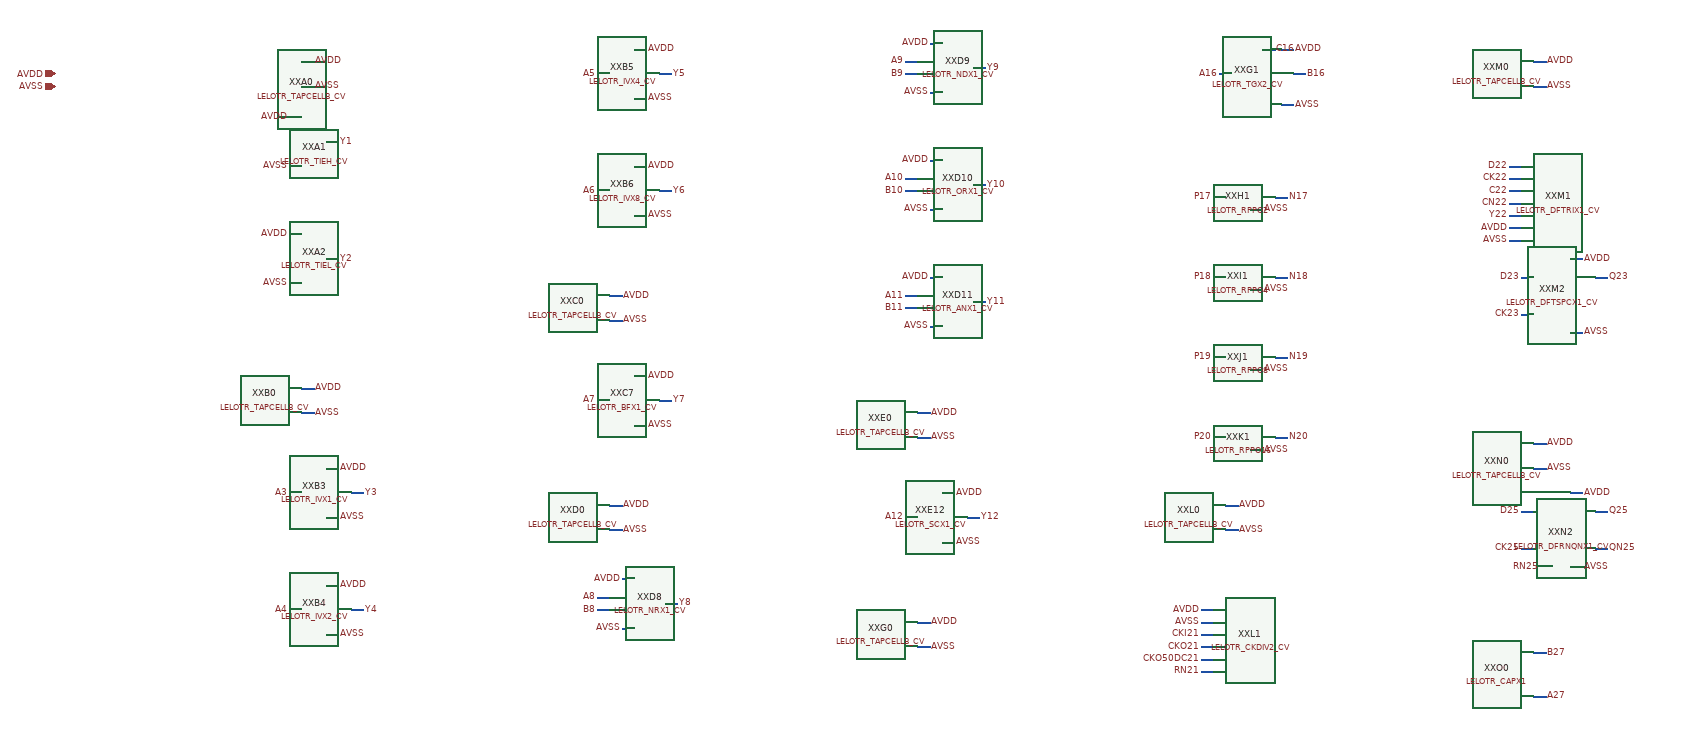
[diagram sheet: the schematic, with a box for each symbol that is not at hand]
v {xschem version=3.0.0 file_version=1.2 }
G {}
K {}
V {}
S {}
E {}
C {devices/iopin.sym} 0 0 0 0 {name=p0 lab=AVDD}
C {devices/iopin.sym} 0 20 0 0 {name=p1 lab=AVSS}
C {LELO_TR_IHP13G2/LELOTR_TAPCELLB_CV.sym} 400 0 0 0 {name=XXA0}
N 420.0 -20.0 400.0 -20.0 {lab=AVDD}
C {devices/lab_pin.sym} 420.0 -20.0 2 0 {name=l0 sig_type=std_logic lab=AVDD }
N 420.0 20.0 400.0 20.0 {lab=AVSS}
C {devices/lab_pin.sym} 420.0 20.0 2 0 {name=l1 sig_type=std_logic lab=AVSS }
C {LELO_TR_IHP13G2/LELOTR_TIEH_CV.sym} 400 150.0 0 0 {name=XXA1}
N 460.0 110.0 440.0 110.0 {lab=Y1}
C {devices/lab_pin.sym} 460.0 110.0 2 0 {name=l2 sig_type=std_logic lab=Y1 }
N 380.0 70.0 400.0 70.0 {lab=AVDD}
C {devices/lab_pin.sym} 380.0 70.0 0 0 {name=l3 sig_type=std_logic lab=AVDD }
N 380.0 150.0 400.0 150.0 {lab=AVSS}
C {devices/lab_pin.sym} 380.0 150.0 0 0 {name=l4 sig_type=std_logic lab=AVSS }
C {LELO_TR_IHP13G2/LELOTR_TIEL_CV.sym} 400 340.0 0 0 {name=XXA2}
N 460.0 300.0 440.0 300.0 {lab=Y2}
C {devices/lab_pin.sym} 460.0 300.0 2 0 {name=l5 sig_type=std_logic lab=Y2 }
N 380.0 260.0 400.0 260.0 {lab=AVDD}
C {devices/lab_pin.sym} 380.0 260.0 0 0 {name=l6 sig_type=std_logic lab=AVDD }
N 380.0 340.0 400.0 340.0 {lab=AVSS}
C {devices/lab_pin.sym} 380.0 340.0 0 0 {name=l7 sig_type=std_logic lab=AVSS }
C {LELO_TR_IHP13G2/LELOTR_TAPCELLB_CV.sym} 400 530.0 0 0 {name=XXB0}
N 420.0 510.0 400.0 510.0 {lab=AVDD}
C {devices/lab_pin.sym} 420.0 510.0 2 0 {name=l8 sig_type=std_logic lab=AVDD }
N 420.0 550.0 400.0 550.0 {lab=AVSS}
C {devices/lab_pin.sym} 420.0 550.0 2 0 {name=l9 sig_type=std_logic lab=AVSS }
C {LELO_TR_IHP13G2/LELOTR_IVX1_CV.sym} 400 680.0 0 0 {name=XXB3}
N 380.0 680.0 400.0 680.0 {lab=A3}
C {devices/lab_pin.sym} 380.0 680.0 0 0 {name=l10 sig_type=std_logic lab=A3 }
N 500.0 680.0 480.0 680.0 {lab=Y3}
C {devices/lab_pin.sym} 500.0 680.0 2 0 {name=l11 sig_type=std_logic lab=Y3 }
N 460.0 640.0 440.0 640.0 {lab=AVDD}
C {devices/lab_pin.sym} 460.0 640.0 2 0 {name=l12 sig_type=std_logic lab=AVDD }
N 460.0 720.0 440.0 720.0 {lab=AVSS}
C {devices/lab_pin.sym} 460.0 720.0 2 0 {name=l13 sig_type=std_logic lab=AVSS }
C {LELO_TR_IHP13G2/LELOTR_IVX2_CV.sym} 400 870.0 0 0 {name=XXB4}
N 380.0 870.0 400.0 870.0 {lab=A4}
C {devices/lab_pin.sym} 380.0 870.0 0 0 {name=l14 sig_type=std_logic lab=A4 }
N 500.0 870.0 480.0 870.0 {lab=Y4}
C {devices/lab_pin.sym} 500.0 870.0 2 0 {name=l15 sig_type=std_logic lab=Y4 }
N 460.0 830.0 440.0 830.0 {lab=AVDD}
C {devices/lab_pin.sym} 460.0 830.0 2 0 {name=l16 sig_type=std_logic lab=AVDD }
N 460.0 910.0 440.0 910.0 {lab=AVSS}
C {devices/lab_pin.sym} 460.0 910.0 2 0 {name=l17 sig_type=std_logic lab=AVSS }
C {LELO_TR_IHP13G2/LELOTR_IVX4_CV.sym} 900 0 0 0 {name=XXB5}
N 880.0 0.0 900.0 0.0 {lab=A5}
C {devices/lab_pin.sym} 880.0 0.0 0 0 {name=l18 sig_type=std_logic lab=A5 }
N 1000.0 0.0 980.0 0.0 {lab=Y5}
C {devices/lab_pin.sym} 1000.0 0.0 2 0 {name=l19 sig_type=std_logic lab=Y5 }
N 960.0 -40.0 940.0 -40.0 {lab=AVDD}
C {devices/lab_pin.sym} 960.0 -40.0 2 0 {name=l20 sig_type=std_logic lab=AVDD }
N 960.0 40.0 940.0 40.0 {lab=AVSS}
C {devices/lab_pin.sym} 960.0 40.0 2 0 {name=l21 sig_type=std_logic lab=AVSS }
C {LELO_TR_IHP13G2/LELOTR_IVX8_CV.sym} 900 190.0 0 0 {name=XXB6}
N 880.0 190.0 900.0 190.0 {lab=A6}
C {devices/lab_pin.sym} 880.0 190.0 0 0 {name=l22 sig_type=std_logic lab=A6 }
N 1000.0 190.0 980.0 190.0 {lab=Y6}
C {devices/lab_pin.sym} 1000.0 190.0 2 0 {name=l23 sig_type=std_logic lab=Y6 }
N 960.0 150.0 940.0 150.0 {lab=AVDD}
C {devices/lab_pin.sym} 960.0 150.0 2 0 {name=l24 sig_type=std_logic lab=AVDD }
N 960.0 230.0 940.0 230.0 {lab=AVSS}
C {devices/lab_pin.sym} 960.0 230.0 2 0 {name=l25 sig_type=std_logic lab=AVSS }
C {LELO_TR_IHP13G2/LELOTR_TAPCELLB_CV.sym} 900 380.0 0 0 {name=XXC0}
N 920.0 360.0 900.0 360.0 {lab=AVDD}
C {devices/lab_pin.sym} 920.0 360.0 2 0 {name=l26 sig_type=std_logic lab=AVDD }
N 920.0 400.0 900.0 400.0 {lab=AVSS}
C {devices/lab_pin.sym} 920.0 400.0 2 0 {name=l27 sig_type=std_logic lab=AVSS }
C {LELO_TR_IHP13G2/LELOTR_BFX1_CV.sym} 900 530.0 0 0 {name=XXC7}
N 880.0 530.0 900.0 530.0 {lab=A7}
C {devices/lab_pin.sym} 880.0 530.0 0 0 {name=l28 sig_type=std_logic lab=A7 }
N 1000.0 530.0 980.0 530.0 {lab=Y7}
C {devices/lab_pin.sym} 1000.0 530.0 2 0 {name=l29 sig_type=std_logic lab=Y7 }
N 960.0 490.0 940.0 490.0 {lab=AVDD}
C {devices/lab_pin.sym} 960.0 490.0 2 0 {name=l30 sig_type=std_logic lab=AVDD }
N 960.0 570.0 940.0 570.0 {lab=AVSS}
C {devices/lab_pin.sym} 960.0 570.0 2 0 {name=l31 sig_type=std_logic lab=AVSS }
C {LELO_TR_IHP13G2/LELOTR_TAPCELLB_CV.sym} 900 720.0 0 0 {name=XXD0}
N 920.0 700.0 900.0 700.0 {lab=AVDD}
C {devices/lab_pin.sym} 920.0 700.0 2 0 {name=l32 sig_type=std_logic lab=AVDD }
N 920.0 740.0 900.0 740.0 {lab=AVSS}
C {devices/lab_pin.sym} 920.0 740.0 2 0 {name=l33 sig_type=std_logic lab=AVSS }
C {LELO_TR_IHP13G2/LELOTR_NRX1_CV.sym} 900 870.0 0 0 {name=XXD8}
N 880.0 850.0 900.0 850.0 {lab=A8}
C {devices/lab_pin.sym} 880.0 850.0 0 0 {name=l34 sig_type=std_logic lab=A8 }
N 880.0 870.0 900.0 870.0 {lab=B8}
C {devices/lab_pin.sym} 880.0 870.0 0 0 {name=l35 sig_type=std_logic lab=B8 }
N 1010.0 860.0 990.0 860.0 {lab=Y8}
C {devices/lab_pin.sym} 1010.0 860.0 2 0 {name=l36 sig_type=std_logic lab=Y8 }
N 920.0 820.0 940.0 820.0 {lab=AVDD}
C {devices/lab_pin.sym} 920.0 820.0 0 0 {name=l37 sig_type=std_logic lab=AVDD }
N 920.0 900.0 940.0 900.0 {lab=AVSS}
C {devices/lab_pin.sym} 920.0 900.0 0 0 {name=l38 sig_type=std_logic lab=AVSS }
C {LELO_TR_IHP13G2/LELOTR_NDX1_CV.sym} 1400 0 0 0 {name=XXD9}
N 1380.0 -20.0 1400.0 -20.0 {lab=A9}
C {devices/lab_pin.sym} 1380.0 -20.0 0 0 {name=l39 sig_type=std_logic lab=A9 }
N 1380.0 0.0 1400.0 0.0 {lab=B9}
C {devices/lab_pin.sym} 1380.0 0.0 0 0 {name=l40 sig_type=std_logic lab=B9 }
N 1510.0 -10.0 1490.0 -10.0 {lab=Y9}
C {devices/lab_pin.sym} 1510.0 -10.0 2 0 {name=l41 sig_type=std_logic lab=Y9 }
N 1420.0 -50.0 1440.0 -50.0 {lab=AVDD}
C {devices/lab_pin.sym} 1420.0 -50.0 0 0 {name=l42 sig_type=std_logic lab=AVDD }
N 1420.0 30.0 1440.0 30.0 {lab=AVSS}
C {devices/lab_pin.sym} 1420.0 30.0 0 0 {name=l43 sig_type=std_logic lab=AVSS }
C {LELO_TR_IHP13G2/LELOTR_ORX1_CV.sym} 1400 190.0 0 0 {name=XXD10}
N 1380.0 170.0 1400.0 170.0 {lab=A10}
C {devices/lab_pin.sym} 1380.0 170.0 0 0 {name=l44 sig_type=std_logic lab=A10 }
N 1380.0 190.0 1400.0 190.0 {lab=B10}
C {devices/lab_pin.sym} 1380.0 190.0 0 0 {name=l45 sig_type=std_logic lab=B10 }
N 1510.0 180.0 1490.0 180.0 {lab=Y10}
C {devices/lab_pin.sym} 1510.0 180.0 2 0 {name=l46 sig_type=std_logic lab=Y10 }
N 1420.0 140.0 1440.0 140.0 {lab=AVDD}
C {devices/lab_pin.sym} 1420.0 140.0 0 0 {name=l47 sig_type=std_logic lab=AVDD }
N 1420.0 220.0 1440.0 220.0 {lab=AVSS}
C {devices/lab_pin.sym} 1420.0 220.0 0 0 {name=l48 sig_type=std_logic lab=AVSS }
C {LELO_TR_IHP13G2/LELOTR_ANX1_CV.sym} 1400 380.0 0 0 {name=XXD11}
N 1380.0 360.0 1400.0 360.0 {lab=A11}
C {devices/lab_pin.sym} 1380.0 360.0 0 0 {name=l49 sig_type=std_logic lab=A11 }
N 1380.0 380.0 1400.0 380.0 {lab=B11}
C {devices/lab_pin.sym} 1380.0 380.0 0 0 {name=l50 sig_type=std_logic lab=B11 }
N 1510.0 370.0 1490.0 370.0 {lab=Y11}
C {devices/lab_pin.sym} 1510.0 370.0 2 0 {name=l51 sig_type=std_logic lab=Y11 }
N 1420.0 330.0 1440.0 330.0 {lab=AVDD}
C {devices/lab_pin.sym} 1420.0 330.0 0 0 {name=l52 sig_type=std_logic lab=AVDD }
N 1420.0 410.0 1440.0 410.0 {lab=AVSS}
C {devices/lab_pin.sym} 1420.0 410.0 0 0 {name=l53 sig_type=std_logic lab=AVSS }
C {LELO_TR_IHP13G2/LELOTR_TAPCELLB_CV.sym} 1400 570.0 0 0 {name=XXE0}
N 1420.0 550.0 1400.0 550.0 {lab=AVDD}
C {devices/lab_pin.sym} 1420.0 550.0 2 0 {name=l54 sig_type=std_logic lab=AVDD }
N 1420.0 590.0 1400.0 590.0 {lab=AVSS}
C {devices/lab_pin.sym} 1420.0 590.0 2 0 {name=l55 sig_type=std_logic lab=AVSS }
C {LELO_TR_IHP13G2/LELOTR_SCX1_CV.sym} 1400 720.0 0 0 {name=XXE12}
N 1380.0 720.0 1400.0 720.0 {lab=A12}
C {devices/lab_pin.sym} 1380.0 720.0 0 0 {name=l56 sig_type=std_logic lab=A12 }
N 1500.0 720.0 1480.0 720.0 {lab=Y12}
C {devices/lab_pin.sym} 1500.0 720.0 2 0 {name=l57 sig_type=std_logic lab=Y12 }
N 1460.0 680.0 1440.0 680.0 {lab=AVDD}
C {devices/lab_pin.sym} 1460.0 680.0 2 0 {name=l58 sig_type=std_logic lab=AVDD }
N 1460.0 760.0 1440.0 760.0 {lab=AVSS}
C {devices/lab_pin.sym} 1460.0 760.0 2 0 {name=l59 sig_type=std_logic lab=AVSS }
C {LELO_TR_IHP13G2/LELOTR_TAPCELLB_CV.sym} 1400 910.0 0 0 {name=XXG0}
N 1420.0 890.0 1400.0 890.0 {lab=AVDD}
C {devices/lab_pin.sym} 1420.0 890.0 2 0 {name=l60 sig_type=std_logic lab=AVDD }
N 1420.0 930.0 1400.0 930.0 {lab=AVSS}
C {devices/lab_pin.sym} 1420.0 930.0 2 0 {name=l61 sig_type=std_logic lab=AVSS }
C {LELO_TR_IHP13G2/LELOTR_TGX2_CV.sym} 1900 0 0 0 {name=XXG1}
N 1890.0 0.0 1910.0 0.0 {lab=A16}
C {devices/lab_pin.sym} 1890.0 0.0 0 0 {name=l62 sig_type=std_logic lab=A16 }
N 1980.0 -40.0 1960.0 -40.0 {lab=C16}
C {devices/lab_pin.sym} 1980.0 -40.0 2 0 {name=l63 sig_type=std_logic lab=C16 }
N 2030.0 0.0 2010.0 0.0 {lab=B16}
C {devices/lab_pin.sym} 2030.0 0.0 2 0 {name=l64 sig_type=std_logic lab=B16 }
N 2010.0 -40.0 1990.0 -40.0 {lab=AVDD}
C {devices/lab_pin.sym} 2010.0 -40.0 2 0 {name=l65 sig_type=std_logic lab=AVDD }
N 2010.0 50.0 1990.0 50.0 {lab=AVSS}
C {devices/lab_pin.sym} 2010.0 50.0 2 0 {name=l66 sig_type=std_logic lab=AVSS }
C {LELO_TR_IHP13G2/LELOTR_RPPO2.sym} 1900 200.0 0 0 {name=XXH1}
N 1880.0 200.0 1900.0 200.0 {lab=P17}
C {devices/lab_pin.sym} 1880.0 200.0 0 0 {name=l67 sig_type=std_logic lab=P17 }
N 2000.0 200.0 1980.0 200.0 {lab=N17}
C {devices/lab_pin.sym} 2000.0 200.0 2 0 {name=l68 sig_type=std_logic lab=N17 }
N 1960.0 220.0 1940.0 220.0 {lab=AVSS}
C {devices/lab_pin.sym} 1960.0 220.0 2 0 {name=l69 sig_type=std_logic lab=AVSS }
C {LELO_TR_IHP13G2/LELOTR_RPPO4.sym} 1900 330.0 0 0 {name=XXI1}
N 1880.0 330.0 1900.0 330.0 {lab=P18}
C {devices/lab_pin.sym} 1880.0 330.0 0 0 {name=l70 sig_type=std_logic lab=P18 }
N 2000.0 330.0 1980.0 330.0 {lab=N18}
C {devices/lab_pin.sym} 2000.0 330.0 2 0 {name=l71 sig_type=std_logic lab=N18 }
N 1960.0 350.0 1940.0 350.0 {lab=AVSS}
C {devices/lab_pin.sym} 1960.0 350.0 2 0 {name=l72 sig_type=std_logic lab=AVSS }
C {LELO_TR_IHP13G2/LELOTR_RPPO8.sym} 1900 460.0 0 0 {name=XXJ1}
N 1880.0 460.0 1900.0 460.0 {lab=P19}
C {devices/lab_pin.sym} 1880.0 460.0 0 0 {name=l73 sig_type=std_logic lab=P19 }
N 2000.0 460.0 1980.0 460.0 {lab=N19}
C {devices/lab_pin.sym} 2000.0 460.0 2 0 {name=l74 sig_type=std_logic lab=N19 }
N 1960.0 480.0 1940.0 480.0 {lab=AVSS}
C {devices/lab_pin.sym} 1960.0 480.0 2 0 {name=l75 sig_type=std_logic lab=AVSS }
C {LELO_TR_IHP13G2/LELOTR_RPPO16.sym} 1900 590.0 0 0 {name=XXK1}
N 1880.0 590.0 1900.0 590.0 {lab=P20}
C {devices/lab_pin.sym} 1880.0 590.0 0 0 {name=l76 sig_type=std_logic lab=P20 }
N 2000.0 590.0 1980.0 590.0 {lab=N20}
C {devices/lab_pin.sym} 2000.0 590.0 2 0 {name=l77 sig_type=std_logic lab=N20 }
N 1960.0 610.0 1940.0 610.0 {lab=AVSS}
C {devices/lab_pin.sym} 1960.0 610.0 2 0 {name=l78 sig_type=std_logic lab=AVSS }
C {LELO_TR_IHP13G2/LELOTR_TAPCELLB_CV.sym} 1900 720.0 0 0 {name=XXL0}
N 1920.0 700.0 1900.0 700.0 {lab=AVDD}
C {devices/lab_pin.sym} 1920.0 700.0 2 0 {name=l79 sig_type=std_logic lab=AVDD }
N 1920.0 740.0 1900.0 740.0 {lab=AVSS}
C {devices/lab_pin.sym} 1920.0 740.0 2 0 {name=l80 sig_type=std_logic lab=AVSS }
C {LELO_TR_IHP13G2/LELOTR_CKDIV2_CV.sym} 1900 870.0 0 0 {name=XXL1}
N 1860.0 870.0 1880.0 870.0 {lab=AVDD}
C {devices/lab_pin.sym} 1860.0 870.0 0 0 {name=l81 sig_type=std_logic lab=AVDD }
N 1860.0 890.0 1880.0 890.0 {lab=AVSS}
C {devices/lab_pin.sym} 1860.0 890.0 0 0 {name=l82 sig_type=std_logic lab=AVSS }
N 1860.0 910.0 1880.0 910.0 {lab=CKI21}
C {devices/lab_pin.sym} 1860.0 910.0 0 0 {name=l83 sig_type=std_logic lab=CKI21 }
N 1860.0 930.0 1880.0 930.0 {lab=CKO21}
C {devices/lab_pin.sym} 1860.0 930.0 0 0 {name=l84 sig_type=std_logic lab=CKO21 }
N 1860.0 950.0 1880.0 950.0 {lab=CKO50DC21}
C {devices/lab_pin.sym} 1860.0 950.0 0 0 {name=l85 sig_type=std_logic lab=CKO50DC21 }
N 1860.0 970.0 1880.0 970.0 {lab=RN21}
C {devices/lab_pin.sym} 1860.0 970.0 0 0 {name=l86 sig_type=std_logic lab=RN21 }
C {LELO_TR_IHP13G2/LELOTR_TAPCELLB_CV.sym} 2400 0 0 0 {name=XXM0}
N 2420.0 -20.0 2400.0 -20.0 {lab=AVDD}
C {devices/lab_pin.sym} 2420.0 -20.0 2 0 {name=l87 sig_type=std_logic lab=AVDD }
N 2420.0 20.0 2400.0 20.0 {lab=AVSS}
C {devices/lab_pin.sym} 2420.0 20.0 2 0 {name=l88 sig_type=std_logic lab=AVSS }
C {LELO_TR_IHP13G2/LELOTR_DFTRIX1_CV.sym} 2400 150.0 0 0 {name=XXM1}
N 2360.0 150.0 2380.0 150.0 {lab=D22}
C {devices/lab_pin.sym} 2360.0 150.0 0 0 {name=l89 sig_type=std_logic lab=D22 }
N 2360.0 170.0 2380.0 170.0 {lab=CK22}
C {devices/lab_pin.sym} 2360.0 170.0 0 0 {name=l90 sig_type=std_logic lab=CK22 }
N 2360.0 190.0 2380.0 190.0 {lab=C22}
C {devices/lab_pin.sym} 2360.0 190.0 0 0 {name=l91 sig_type=std_logic lab=C22 }
N 2360.0 210.0 2380.0 210.0 {lab=CN22}
C {devices/lab_pin.sym} 2360.0 210.0 0 0 {name=l92 sig_type=std_logic lab=CN22 }
N 2360.0 230.0 2380.0 230.0 {lab=Y22}
C {devices/lab_pin.sym} 2360.0 230.0 0 0 {name=l93 sig_type=std_logic lab=Y22 }
N 2360.0 250.0 2380.0 250.0 {lab=AVDD}
C {devices/lab_pin.sym} 2360.0 250.0 0 0 {name=l94 sig_type=std_logic lab=AVDD }
N 2360.0 270.0 2380.0 270.0 {lab=AVSS}
C {devices/lab_pin.sym} 2360.0 270.0 0 0 {name=l95 sig_type=std_logic lab=AVSS }
C {LELO_TR_IHP13G2/LELOTR_DFTSPCX1_CV.sym} 2400 390.0 0 0 {name=XXM2}
N 2380.0 330.0 2400.0 330.0 {lab=D23}
C {devices/lab_pin.sym} 2380.0 330.0 0 0 {name=l96 sig_type=std_logic lab=D23 }
N 2380.0 390.0 2400.0 390.0 {lab=CK23}
C {devices/lab_pin.sym} 2380.0 390.0 0 0 {name=l97 sig_type=std_logic lab=CK23 }
N 2520.0 330.0 2500.0 330.0 {lab=Q23}
C {devices/lab_pin.sym} 2520.0 330.0 2 0 {name=l98 sig_type=std_logic lab=Q23 }
N 2480.0 300.0 2460.0 300.0 {lab=AVDD}
C {devices/lab_pin.sym} 2480.0 300.0 2 0 {name=l99 sig_type=std_logic lab=AVDD }
N 2480.0 420.0 2460.0 420.0 {lab=AVSS}
C {devices/lab_pin.sym} 2480.0 420.0 2 0 {name=l100 sig_type=std_logic lab=AVSS }
C {LELO_TR_IHP13G2/LELOTR_TAPCELLB_CV.sym} 2400 620.0 0 0 {name=XXN0}
N 2420.0 600.0 2400.0 600.0 {lab=AVDD}
C {devices/lab_pin.sym} 2420.0 600.0 2 0 {name=l101 sig_type=std_logic lab=AVDD }
N 2420.0 640.0 2400.0 640.0 {lab=AVSS}
C {devices/lab_pin.sym} 2420.0 640.0 2 0 {name=l102 sig_type=std_logic lab=AVSS }
C {LELO_TR_IHP13G2/LELOTR_DFRNQNX1_CV.sym} 2400 770.0 0 0 {name=XXN2}
N 2380.0 710.0 2400.0 710.0 {lab=D25}
C {devices/lab_pin.sym} 2380.0 710.0 0 0 {name=l103 sig_type=std_logic lab=D25 }
N 2380.0 770.0 2400.0 770.0 {lab=CK25}
C {devices/lab_pin.sym} 2380.0 770.0 0 0 {name=l104 sig_type=std_logic lab=CK25 }
N 2410.0 800.0 2430.0 800.0 {lab=RN25}
C {devices/lab_pin.sym} 2410.0 800.0 0 0 {name=l105 sig_type=std_logic lab=RN25 }
N 2520.0 710.0 2500.0 710.0 {lab=Q25}
C {devices/lab_pin.sym} 2520.0 710.0 2 0 {name=l106 sig_type=std_logic lab=Q25 }
N 2520.0 770.0 2500.0 770.0 {lab=QN25}
C {devices/lab_pin.sym} 2520.0 770.0 2 0 {name=l107 sig_type=std_logic lab=QN25 }
N 2480.0 680.0 2460.0 680.0 {lab=AVDD}
C {devices/lab_pin.sym} 2480.0 680.0 2 0 {name=l108 sig_type=std_logic lab=AVDD }
N 2480.0 800.0 2460.0 800.0 {lab=AVSS}
C {devices/lab_pin.sym} 2480.0 800.0 2 0 {name=l109 sig_type=std_logic lab=AVSS }
C {LELO_TR_IHP13G2/LELOTR_CAPX1.sym} 2400 1000.0 0 0 {name=XXO0}
N 2420.0 1010.0 2400.0 1010.0 {lab=A27}
C {devices/lab_pin.sym} 2420.0 1010.0 2 0 {name=l110 sig_type=std_logic lab=A27 }
N 2420.0 940.0 2400.0 940.0 {lab=B27}
C {devices/lab_pin.sym} 2420.0 940.0 2 0 {name=l111 sig_type=std_logic lab=B27 }
